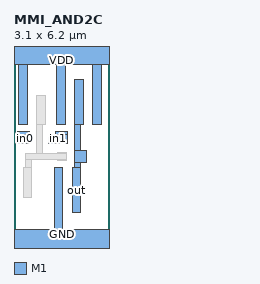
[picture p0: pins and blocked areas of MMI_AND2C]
MACRO MMI_AND2C
	CLASS CORE ;
	FOREIGN MMI_AND2C 0 0 ;
	SIZE 3.1 BY 6.2 ;
	SYMMETRY X Y ;
	SITE CORE1 ;
	PIN out
		DIRECTION output ;
		USE SIGNAL ;
		PORT
			LAYER M1 ;
			RECT 1.985 3.82 2.265 5.29 ;
			LAYER M1 ;
			RECT 1.99 2.98 2.18 3.82 ;
			LAYER M1 ;
			RECT 1.99 2.6 2.36 2.98 ;
			LAYER M1 ;
			RECT 1.99 2.43 2.18 2.6 ;
			LAYER M1 ;
			RECT 1.9 0.96 2.18 2.43 ;
		END
		AntennaDiffArea 1.2859 ;
	END out
	PIN in1
		DIRECTION input ;
		USE SIGNAL ;
		PORT
			LAYER M1 ;
			RECT 1.36 3.51 1.74 3.6 ;
			LAYER M1 ;
			RECT 1.135 3.23 1.74 3.51 ;
			LAYER M1 ;
			RECT 1.36 3.22 1.74 3.23 ;
		END
		AntennaGateArea 0.312 ;
	END in1
	PIN GND
		DIRECTION inout ;
		USE GROUND ;
		PORT
			LAYER M1 ;
			RECT 1.31 0.42 1.59 2.43 ;
			LAYER M1 ;
			RECT 0 -0.42 3.1 0.42 ;
		END
	END GND
	PIN VDD
		DIRECTION inout ;
		USE POWER ;
		PORT
			LAYER M1 ;
			RECT 0 5.78 3.1 6.62 ;
			LAYER M1 ;
			RECT 0.155 3.82 0.435 5.78 ;
			LAYER M1 ;
			RECT 1.395 3.82 1.675 5.78 ;
			LAYER M1 ;
			RECT 2.575 3.82 2.855 5.78 ;
		END
	END VDD
	PIN in0
		DIRECTION input ;
		USE SIGNAL ;
		PORT
			LAYER M1 ;
			RECT 0.12 3.51 0.5 3.6 ;
			LAYER M1 ;
			RECT 0.12 3.23 0.505 3.51 ;
			LAYER M1 ;
			RECT 0.12 3.22 0.5 3.23 ;
		END
		AntennaGateArea 0.312 ;
	END in0
	OBS
		LAYER M1 ;
		RECT 0.745 3.82 1.025 4.79 ;
		LAYER M1 ;
		RECT 0.745 2.885 0.935 3.82 ;
		LAYER M1 ;
		RECT 1.435 2.885 1.715 2.93 ;
		LAYER M1 ;
		RECT 0.39 2.695 1.715 2.885 ;
		LAYER M1 ;
		RECT 0.39 2.435 0.58 2.695 ;
		LAYER M1 ;
		RECT 1.435 2.65 1.715 2.695 ;
		LAYER M1 ;
		RECT 0.3 1.465 0.58 2.435 ;
	END
END MMI_AND2C
